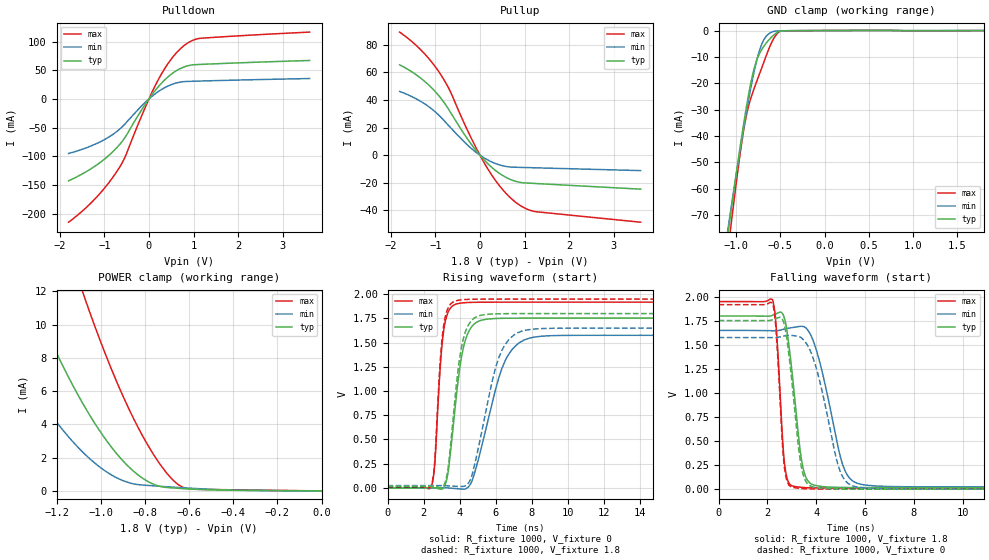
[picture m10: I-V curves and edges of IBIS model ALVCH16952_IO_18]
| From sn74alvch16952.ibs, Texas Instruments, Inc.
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[Model]   ALVCH16952_IO_18
Model_type  I/O
Vinl=0.5775
Vinh=1.2675
Enable   Active-Low
Vref =   0
Rref =   1000
Cref =   30p
Vmeas =   0.9
| variable   typ   min   max
C_comp   9.04pF   7.94pF   9.91pF
| C_pullup   10.14pF   8.52pF   10.95pF
| C_pulldown   13.73pF   10.32pF   17.69pF
| C_tri-state   9.04pF   7.94pF   9.91pF
[Temperature Range]   40   100   -40
| Ambient temperature   25   85   -40
[Voltage range]   1.8   1.65   1.95
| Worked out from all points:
|   slope of the pulldown table from 0 to 0.27 V, typ, clamps not added: 10.2 ohm
|   slope of the pullup table from 0 to 0.27 V, typ, clamps not added: 30.2 ohm
|   GND clamp passes 1 mA (typ) near -0.55 V on its own axis
|   POWER clamp passes 1 mA (typ) near -0.83 V on its own axis
|   rising waveform, R_fixture 1000, V_fixture 0: 20-80 % time 677ps typ, 1.34ns min, 389ps max; typ from 0 V to 1.75 V
|   falling waveform, R_fixture 1000, V_fixture 1.8: 20-80 % time 450ps typ, 838ps min, 261ps max; typ from 1.8 V to 0.016 V
|   rising waveform, R_fixture 1000, V_fixture 1.8: 20-80 % time 635ps typ, 1.18ns min, 378ps max; typ from 0.016 V to 1.8 V
|   falling waveform, R_fixture 1000, V_fixture 0: 20-80 % time 438ps typ, 828ps min, 254ps max; typ from 1.75 V to 0 V
[GND Clamp]
| ALVCH16952_IO_18
|   Voltage   I(typ)   I(min)   I(max)
-1.8V     -267.6mA   -247.3mA   -300.9mA
-1.09V    -76.08mA   -74.19mA   -82.29mA
-1.075V   -72.36mA   -70.82mA   -78.07mA
-1.055V   -67.44mA   -66.35mA   -72.5mA
-920mV    -36.15mA   -37.64mA   -38.56mA
-875mV    -26.97mA   -28.87mA   -30.53mA
-820mV    -17.46mA   -19.07mA   -24.06mA
-720mV    -7.641mA   -5.859mA   -14.87mA
-620mV    -3.132mA   -955.8uA   -6.015mA
-555mV    -1.135mA   -206.6uA   -1.909mA
-485mV    -92.05uA   -105.2uA   -123.3uA
1.8V      63.46pA    9.158uA    -21.55uA
[POWER Clamp]
| ALVCH16952_IO_18
|   Voltage   I(typ)   I(min)   I(max)
-1.8V     29.92mA    18.78mA    48.29mA
-1.545V   19.67mA    11.64mA    33.75mA
-1.31V    11.54mA    6.202mA    21.81mA
-1.19V    8.013mA    3.967mA    16.38mA
-1.08V    5.231mA    2.315mA    11.89mA
-1.065V   4.889mA    2.123mA    11.32mA
-925mV    2.195mA    772.6uA    6.48mA
-850mV    1.169mA    421.9uA    4.314mA
-770mV    455.2uA    314.1uA    2.38mA
-695mV    201.7uA    246.4uA    973uA
-635mV    144.5uA    196.4uA    264.5uA
-16.28fV  63.46pA    285.3pA    36.55pA
[Pulldown]
| ALVCH16952_IO_18
|   Voltage   I(typ)   I(min)   I(max)
-1.8V     -142.5mA   -94.94mA   -214.6mA
-1.19V    -116mA     -78.24mA   -172.4mA
-930mV    -100.5mA   -67.79mA   -148.9mA
-690mV    -82.3mA    -54.81mA   -122.9mA
-535mV    -66.97mA   -43.32mA   -101mA
-105mV    -12.13mA   -7.634mA   -18.73mA
200mV     20.41mA    12.38mA    32.16mA
490mV     42.45mA    24.65mA    68.46mA
785mV     55.72mA    30.25mA    92.88mA
970mV     59.35mA    30.84mA    101.8mA
1.155V    60.2mA     31.26mA    105.7mA
3.6V      67.09mA    35.62mA    116.5mA
[Pullup]
| ALVCH16952_IO_18
|   Voltage   I(typ)   I(min)   I(max)
-1.8V     65.54mA    46.25mA    89.25mA
-1.32V    55.67mA    38.89mA    76.19mA
-1.11V    49.72mA    34.29mA    68.65mA
-920mV    43.05mA    29.01mA    60.43mA
-685mV    32.34mA    20.89mA    47.55mA
-250mV    10.47mA    6.526mA    16.03mA
115mV     -4.131mA   -2.38mA    -6.642mA
450mV     -13.44mA   -7.131mA   -22.64mA
790mV     -18.81mA   -8.709mA   -33.84mA
1.02V     -20.1mA    -8.918mA   -38.54mA
1.25V     -20.5mA    -9.124mA   -40.92mA
3.6V      -24.58mA   -11.14mA   -48.53mA
[Ramp]
| ALVCH16952_IO_18
| variable   typ   min   max
dV/dt_r   1.06/6.81E-10   0.95/1.35E-09   1.16/3.93E-10
dV/dt_f   1.10/4.65E-10   1.00/8.68E-10   1.18/2.69E-10
R_load = 1000
[Rising Waveform]
| ALVCH16952_IO_18
R_fixture =   1000
C_fixture =   0
L_fixture =   0
V_fixture =   0
V_fixture_min = 0
V_fixture_max = 0
|   Time   V(typ)   V(min)   V(max)
0s        342.4pV    1.756nV    236.6pV
2.42ns    915.1uV    725.6uV    7.452mV
2.61ns    -498.4uV   993.1uV    230.9mV
3.12ns    5.013mV    937.8uV    1.633V
3.38ns    190.2mV    -660.8uV   1.823V
3.925ns   1.125V     -9.08mV    1.904V
4.835ns   1.697V     159mV      1.916V
6.465ns   1.752V     1.288V     1.918V
8.085ns   1.753V     1.556V     1.918V
50ns      1.753V     1.576V     1.918V
[Falling Waveform]
| ALVCH16952_IO_18
R_fixture =   1000
C_fixture =   0
L_fixture =   0
V_fixture =   1.8
V_fixture_min = 1.65
V_fixture_max = 1.95
|   Time   V(typ)   V(min)   V(max)
0s        1.8V       1.65V      1.95V
2.21ns    1.807V     1.646V     1.969V
2.365ns   1.824V     1.646V     1.672V
2.715ns   1.76V      1.665V     240.2mV
3.175ns   805.7mV    1.686V     26.19mV
3.415ns   280.6mV    1.693V     18.6mV
3.695ns   74.97mV    1.639V     14.52mV
5.115ns   17.66mV    234.4mV    11.27mV
5.99ns    16.31mV    43.33mV    11.11mV
50ns      15.9mV     23.5mV     11.07mV
[Rising Waveform]
| ALVCH16952_IO_18
R_fixture =   1000
C_fixture =   0
L_fixture =   0
V_fixture =   1.8
V_fixture_min = 1.65
V_fixture_max = 1.95
|   Time   V(typ)   V(min)   V(max)
0s        15.9mV     23.5mV     11.07mV
2.42ns    16.31mV    24mV       20.08mV
2.605ns   14.82mV    24.03mV    242.7mV
3.105ns   20.21mV    23.31mV    1.667V
3.37ns    217.7mV    21.59mV    1.862V
3.87ns    1.151V     15.55mV    1.936V
4.725ns   1.741V     161.5mV    1.948V
6.195ns   1.798V     1.355V     1.95V
7.705ns   1.8V       1.63V      1.95V
50ns      1.8V       1.65V      1.95V
[Falling Waveform]
| ALVCH16952_IO_18
R_fixture =   1000
C_fixture =   0
L_fixture =   0
V_fixture =   0
V_fixture_min = 0
V_fixture_max = 0
|   Time   V(typ)   V(min)   V(max)
0s        1.753V     1.576V     1.918V
2.21ns    1.761V     1.575V     1.932V
2.36ns    1.775V     1.576V     1.636V
2.69ns    1.712V     1.593V     245.8mV
3.08ns    931.2mV    1.595V     16.65mV
3.35ns    294.7mV    1.58V      7.805mV
3.615ns   65.25mV    1.509V     3.534mV
4.97ns    1.604mV    195.9mV    208.9uV
5.795ns   356uV      16.82mV    46.13uV
50ns      334.2nV    654.7nV    158nV
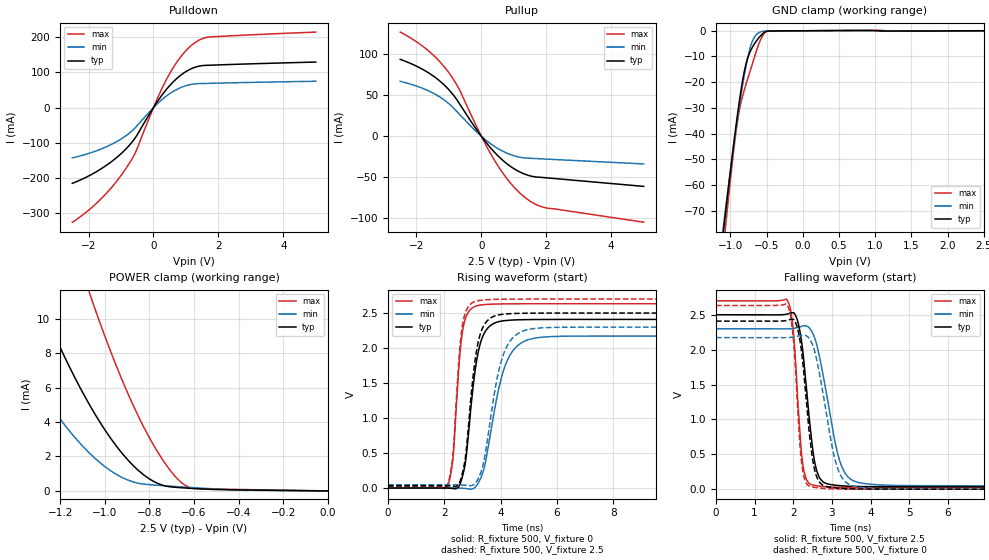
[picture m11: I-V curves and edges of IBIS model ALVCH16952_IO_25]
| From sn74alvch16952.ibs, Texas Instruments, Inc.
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[Model]   ALVCH16952_IO_25
Model_type  I/O
Vinl=0.7
Vinh=1.7
Enable   Active-Low
Vref =   0
Rref =   500
Cref =   30p
Vmeas =   1.25
| variable   typ   min   max
C_comp   8.79pF   7.60pF   9.87pF
| C_pullup   9.95pF   8.18pF   10.94pF
| C_pulldown   13.28pF   10.14pF   17.10pF
| C_tri-state   8.79pF   7.60pF   9.87pF
[Temperature Range]   40   100   -40
| Ambient temperature   25   85   -40
[Voltage range]   2.5   2.3   2.7
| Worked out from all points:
|   slope of the pulldown table from 0 to 0.375 V, typ, clamps not added: 7.66 ohm
|   slope of the pullup table from 0 to 0.375 V, typ, clamps not added: 20.6 ohm
|   GND clamp passes 1 mA (typ) near -0.55 V on its own axis
|   POWER clamp passes 1 mA (typ) near -0.83 V on its own axis
|   rising waveform, R_fixture 500, V_fixture 0: 20-80 % time 412ps typ, 661ps min, 273ps max; typ from 0 V to 2.41 V
|   falling waveform, R_fixture 500, V_fixture 2.5: 20-80 % time 274ps typ, 458ps min, 189ps max; typ from 2.5 V to 0.034 V
|   rising waveform, R_fixture 500, V_fixture 2.5: 20-80 % time 390ps typ, 593ps min, 266ps max; typ from 0.034 V to 2.5 V
|   falling waveform, R_fixture 500, V_fixture 0: 20-80 % time 264ps typ, 427ps min, 178ps max; typ from 2.41 V to 0 V
[GND Clamp]
| ALVCH16952_IO_25
|   Voltage   I(typ)   I(min)   I(max)
-2.5V     -468.2mA   -428.5mA   -529.6mA
-1.095V   -77.37mA   -75.35mA   -83.76mA
-1.08V    -73.64mA   -71.97mA   -79.52mA
-1.06V    -68.71mA   -67.5mA    -73.94mA
-920mV    -36.19mA   -37.67mA   -38.61mA
-870mV    -26.05mA   -27.96mA   -29.86mA
-815mV    -16.76mA   -18.27mA   -23.62mA
-770mV    -11.38mA   -11.52mA   -19.42mA
-710mV    -7.109mA   -5.038mA   -14.01mA
-595mV    -2.305mA   -561.8uA   -4.22mA
-480mV    -108.6uA   -119uA     -144uA
2.5V      87.83pA    19.59uA    -39.6uA
[POWER Clamp]
| ALVCH16952_IO_25
|   Voltage   I(typ)   I(min)   I(max)
-2.5V     63.21mA    42.72mA    94mA
-1.535V   19.34mA    11.42mA    33.27mA
-1.295V   11.11mA    5.931mA    21.15mA
-1.185V   7.912mA    3.912mA    16.21mA
-1.075V   5.149mA    2.277mA    11.74mA
-1.06V    4.81mA     2.088mA    11.17mA
-950mV    2.635mA    975.6uA    7.307mA
-855mV    1.254mA    458.8uA    4.482mA
-745mV    347.8uA    311uA      1.894mA
-655mV    184.1uA    231.1uA    469.9uA
-600mV    137.9uA    185.5uA    146.7uA
-31.15fV  87.83pA    322.1pA    50.73pA
[Pulldown]
| ALVCH16952_IO_25
|   Voltage   I(typ)   I(min)   I(max)
-2.5V     -214.5mA   -142.4mA   -324.7mA
-1.625V   -174.1mA   -117.7mA   -259.4mA
-1.225V   -148.2mA   -100.9mA   -219.1mA
-870mV    -119.2mA   -81.23mA   -175.5mA
-550mV    -84.06mA   -55.7mA    -125.8mA
75mV      10.83mA    7.022mA    16.48mA
430mV     55.09mA    35.04mA    84.84mA
820mV     90.47mA    55.98mA    141.7mA
1.215V    112.2mA    66.71mA    179.9mA
1.465V    118.6mA    68.28mA    193.9mA
1.715V    120.1mA    68.86mA    200.1mA
5V        129.2mA    74.77mA    214.1mA
[Pullup]
| ALVCH16952_IO_25
|   Voltage   I(typ)   I(min)   I(max)
-2.5V     93.89mA    67.09mA    127.2mA
-1.675V   78.56mA    56.27mA    105.7mA
-1.335V   69.15mA    49.28mA    93.27mA
-1.035V   58.23mA    40.89mA    79.35mA
-685mV    40.38mA    27.22mA    57.59mA
15mV      -812.9uA   -531.7uA   -1.2mA
420mV     -20.15mA   -12.8mA    -30.36mA
885mV     -36.42mA   -22.17mA   -56.52mA
1.355V    -46.47mA   -26.53mA   -75.01mA
1.67V     -49.6mA    -27.19mA   -82.95mA
1.985V    -50.63mA   -27.82mA   -87.32mA
5V        -61.14mA   -33.76mA   -104.8mA
[Ramp]
| ALVCH16952_IO_25
| variable   typ   min   max
dV/dt_r   1.45/4.25E-10   1.31/6.68E-10   1.58/2.84E-10
dV/dt_f   1.50/2.82E-10   1.38/4.71E-10   1.62/1.92E-10
R_load = 500
[Rising Waveform]
| ALVCH16952_IO_25
R_fixture =   500
C_fixture =   0
L_fixture =   0
V_fixture =   0
V_fixture_min = 0
V_fixture_max = 0
|   Time   V(typ)   V(min)   V(max)
0s        359.7pV    1.41nV     254.8pV
2.11ns    -384.5uV   1.022mV    21.08mV
2.305ns   -6.264mV   1.284mV    411.1mV
2.535ns   34.68mV    -447.7uV   1.823V
2.675ns   214.9mV    -4.137mV   2.304V
3.085ns   1.647V     7.415mV    2.594V
3.31ns    2.106V     157.1mV    2.616V
4.22ns    2.395V     1.806V     2.632V
5.41ns    2.408V     2.153V     2.633V
50ns      2.409V     2.172V     2.633V
[Falling Waveform]
| ALVCH16952_IO_25
R_fixture =   500
C_fixture =   0
L_fixture =   0
V_fixture =   2.5
V_fixture_min = 2.3
V_fixture_max = 2.7
|   Time   V(typ)   V(min)   V(max)
0s        2.5V       2.3V       2.7V
1.85ns    2.511V     2.298V     2.702V
2.01ns    2.529V     2.305V     2.209V
2.205ns   2.155V     2.332V     568mV
2.27ns    1.856V     2.34V      277.9mV
2.525ns   485.7mV    2.208V     57.2mV
2.755ns   113.4mV    1.684V     37.99mV
3.295ns   46.73mV    275.8mV    26.88mV
4.18ns    35.38mV    62.96mV    24.41mV
50ns      33.66mV    47.57mV    23.96mV
[Rising Waveform]
| ALVCH16952_IO_25
R_fixture =   500
C_fixture =   0
L_fixture =   0
V_fixture =   2.5
V_fixture_min = 2.3
V_fixture_max = 2.7
|   Time   V(typ)   V(min)   V(max)
0s        33.66mV    47.57mV    23.96mV
2.11ns    32.54mV    48.06mV    46.67mV
2.305ns   27.07mV    47.87mV    460.6mV
2.525ns   64.63mV    45.83mV    1.871V
2.66ns    239.9mV    42.44mV    2.363V
3.065ns   1.74V      54.16mV    2.662V
3.285ns   2.209V     208.4mV    2.683V
4.12ns    2.485V     1.931V     2.698V
5.225ns   2.499V     2.281V     2.7V
50ns      2.5V       2.3V       2.7V
[Falling Waveform]
| ALVCH16952_IO_25
R_fixture =   500
C_fixture =   0
L_fixture =   0
V_fixture =   0
V_fixture_min = 0
V_fixture_max = 0
|   Time   V(typ)   V(min)   V(max)
0s        2.409V     2.172V     2.633V
1.845ns   2.42V      2.172V     2.637V
2ns       2.433V     2.179V     2.167V
2.175ns   2.123V     2.198V     611.3mV
2.255ns   1.77V      2.205V     234.9mV
2.5ns     435mV      2.069V     30.4mV
2.72ns    77.32mV    1.528V     12.94mV
3.205ns   12.69mV    221.1mV    2.863mV
4.025ns   1.638mV    13.24mV    492.7uV
50ns      226.9nV    407.1nV    116nV
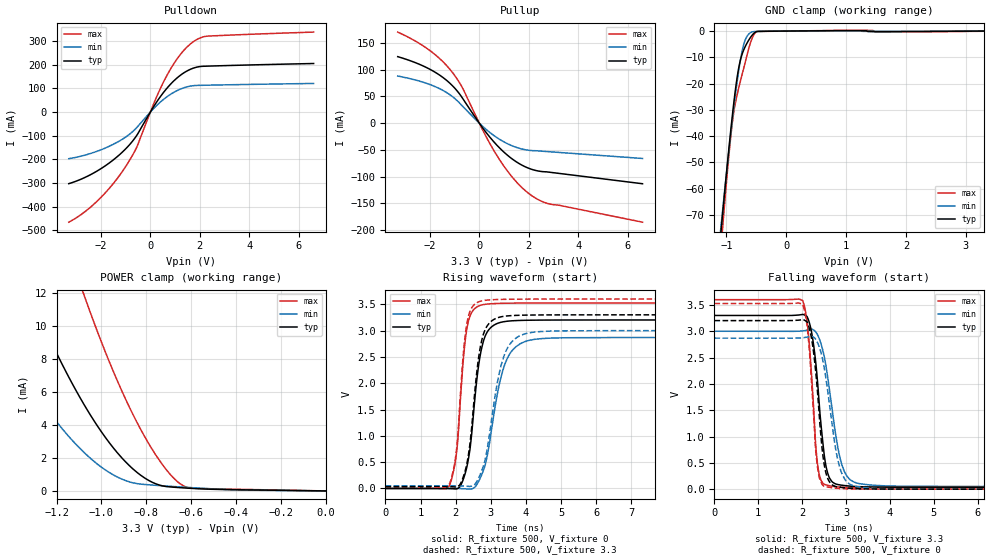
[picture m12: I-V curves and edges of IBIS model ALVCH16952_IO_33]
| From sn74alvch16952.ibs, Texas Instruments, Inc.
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[Model]   ALVCH16952_IO_33
Model_type  I/O
Vinl=0.8
Vinh=2.0
Enable   Active-Low
Vref =   0
Rref =   500
Cref =   50p
Vmeas =   1.5
| variable   typ   min   max
C_comp   8.55pF   7.36pF   9.81pF
| C_pullup   9.70pF   7.97pF   10.77pF
| C_pulldown   12.88pF   10.08pF   16.30pF
| C_tri-state   8.55pF   7.36pF   9.81pF
[Temperature Range]   40   100   -40
| Ambient temperature   25   85   -40
[Voltage range]   3.3   3   3.6
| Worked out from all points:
|   slope of the pulldown table from 0 to 0.495 V, typ, clamps not added: 6.36 ohm
|   slope of the pullup table from 0 to 0.495 V, typ, clamps not added: 16.5 ohm
|   GND clamp passes 1 mA (typ) near -0.55 V on its own axis
|   POWER clamp passes 1 mA (typ) near -0.83 V on its own axis
|   rising waveform, R_fixture 500, V_fixture 0: 20-80 % time 325ps typ, 484ps min, 246ps max; typ from 0 V to 3.2 V
|   falling waveform, R_fixture 500, V_fixture 3.3: 20-80 % time 222ps typ, 321ps min, 169ps max; typ from 3.3 V to 0.037 V
|   rising waveform, R_fixture 500, V_fixture 3.3: 20-80 % time 318ps typ, 456ps min, 243ps max; typ from 0.037 V to 3.3 V
|   falling waveform, R_fixture 500, V_fixture 0: 20-80 % time 207ps typ, 303ps min, 167ps max; typ from 3.2 V to 0 V
[GND Clamp]
| ALVCH16952_IO_33
|   Voltage   I(typ)   I(min)   I(max)
-3.3V     -702.4mA   -640mA     -797mA
-1.09V    -76.16mA   -74.26mA   -82.4mA
-1.07V    -71.21mA   -69.76mA   -76.77mA
-1.05V    -66.3mA    -65.31mA   -71.23mA
-915mV    -35.16mA   -36.7mA    -37.63mA
-865mV    -25.14mA   -27.06mA   -29.22mA
-815mV    -16.79mA   -18.3mA    -23.66mA
-770mV    -11.41mA   -11.55mA   -19.46mA
-710mV    -7.137mA   -5.06mA    -14.05mA
-585mV    -2.015mA   -461.2uA   -3.604mA
-465mV    -118.5uA   -121.8uA   -159.3uA
3.3V      119.5pA    38.6uA     -72.24uA
[POWER Clamp]
| ALVCH16952_IO_33
|   Voltage   I(typ)   I(min)   I(max)
-3.3V     106.7mA    74.57mA    152.5mA
-1.545V   19.75mA    11.71mA    33.86mA
-1.42V    15.24mA    8.652mA    27.3mA
-1.32V    11.93mA    6.464mA    22.37mA
-1.195V   8.217mA    4.105mA    16.68mA
-1.075V   5.177mA    2.3mA      11.77mA
-965mV    2.924mA    1.117mA    7.831mA
-860mV    1.338mA    493uA      4.647mA
-760mV    443.1uA    341.9uA    2.226mA
-660mV    207.7uA    250.2uA    548.6uA
-605mV    159.3uA    203.4uA    176.1uA
-48.03fV  119.5pA    365.4pA    67.97pA
[Pulldown]
| ALVCH16952_IO_33
|   Voltage   I(typ)   I(min)   I(max)
-3.3V     -302.4mA   -196.9mA   -465.1mA
-2.73V    -280.1mA   -184.3mA   -427.4mA
-2.16V    -249.3mA   -165.8mA   -377mA
-1.61V    -210.9mA   -141.8mA   -315.8mA
-1.105V   -166.3mA   -112.9mA   -246.6mA
-565mV    -100.8mA   -67.07mA   -151.3mA
185mV     31.43mA    20.51mA    47.78mA
665mV     100mA      64.12mA    153.8mA
1.165V    151.5mA    94.78mA    236.7mA
1.67V     182.8mA    110.5mA    291.9mA
2.31V     194mA      113.5mA    320.7mA
6.6V      205mA      120.8mA    337.8mA
[Pullup]
| ALVCH16952_IO_33
|   Voltage   I(typ)   I(min)   I(max)
-3.3V     124.6mA    88.26mA    170.5mA
-2.055V   102.2mA    73.29mA    137.8mA
-1.565V   88.69mA    63.61mA    119.2mA
-1.15V    73.01mA    51.93mA    98.57mA
-690mV    47.45mA    32.47mA    66.81mA
180mV     -11.59mA   -7.766mA   -16.76mA
755mV     -43.3mA    -28.29mA   -63.76mA
1.375V    -68.47mA   -43.2mA    -103.3mA
1.995V    -84.31mA   -50.62mA   -131.4mA
2.4V      -89.62mA   -51.95mA   -143.5mA
2.81V     -91.58mA   -53.32mA   -150.8mA
6.6V      -113.3mA   -66.05mA   -185.3mA
[Ramp]
| ALVCH16952_IO_33
| variable   typ   min   max
dV/dt_r   1.93/3.36E-10   1.73/4.95E-10   2.12/2.49E-10
dV/dt_f   1.97/2.30E-10   1.79/3.30E-10   2.15/1.79E-10
R_load = 500
[Rising Waveform]
| ALVCH16952_IO_33
R_fixture =   500
C_fixture =   0
L_fixture =   0
V_fixture =   0
V_fixture_min = 0
V_fixture_max = 0
|   Time   V(typ)   V(min)   V(max)
0s        394.8pV    1.292nV    283.4pV
1.815ns   -1.851mV   1.2mV      48mV
2.035ns   -4.87mV    184.4uV    748.6mV
2.21ns    164.7mV    -4.469mV   2.397V
2.34ns    482.1mV    -9.666mV   3.114V
2.665ns   2.395V     151.4mV    3.471V
2.895ns   2.971V     612.8mV    3.505V
3.47ns    3.179V     2.474V     3.521V
4.46ns    3.2V       2.849V     3.525V
50ns      3.202V     2.869V     3.526V
[Falling Waveform]
| ALVCH16952_IO_33
R_fixture =   500
C_fixture =   0
L_fixture =   0
V_fixture =   3.3
V_fixture_min = 3
V_fixture_max = 3.6
|   Time   V(typ)   V(min)   V(max)
0s        3.3V       3V         3.6V
2.01ns    3.319V     3.006V     3.583V
2.11ns    3.281V     3.018V     3.204V
2.21ns    3.002V     3.041V     2.217V
2.38ns    1.728V     2.879V     316.7mV
2.555ns   390.5mV    2.275V     78.68mV
2.815ns   87.59mV    786.5mV    43.01mV
3.11ns    56.88mV    169.2mV    32.48mV
4.11ns    38.66mV    58.25mV    27.3mV
50ns      37.01mV    51.21mV    26.69mV
[Rising Waveform]
| ALVCH16952_IO_33
R_fixture =   500
C_fixture =   0
L_fixture =   0
V_fixture =   3.3
V_fixture_min = 3
V_fixture_max = 3.6
|   Time   V(typ)   V(min)   V(max)
0s        37.01mV    51.21mV    26.69mV
1.8ns     35.14mV    51.86mV    63.82mV
1.995ns   28.68mV    51.15mV    586mV
2.125ns   78.92mV    48.16mV    1.7V
2.365ns   655.3mV    40.2mV     3.282V
2.65ns    2.475V     194.6mV    3.546V
2.87ns    3.06V      650.3mV    3.579V
3.415ns   3.276V     2.587V     3.595V
4.38ns    3.298V     2.981V     3.599V
50ns      3.3V       3V         3.6V
[Falling Waveform]
| ALVCH16952_IO_33
R_fixture =   500
C_fixture =   0
L_fixture =   0
V_fixture =   0
V_fixture_min = 0
V_fixture_max = 0
|   Time   V(typ)   V(min)   V(max)
0s        3.202V     2.869V     3.526V
2.01ns    3.221V     2.876V     3.507V
2.11ns    3.178V     2.888V     3.117V
2.21ns    2.884V     2.906V     2.071V
2.38ns    1.518V     2.724V     268.3mV
2.535ns   332.4mV    2.142V     50.2mV
2.8ns     44.53mV    607.8mV    15.27mV
3.1ns     16.52mV    87.12mV    5.166mV
4.045ns   1.463mV    5.537mV    597uV
50ns      176.6nV    313.1nV    89.91nV
